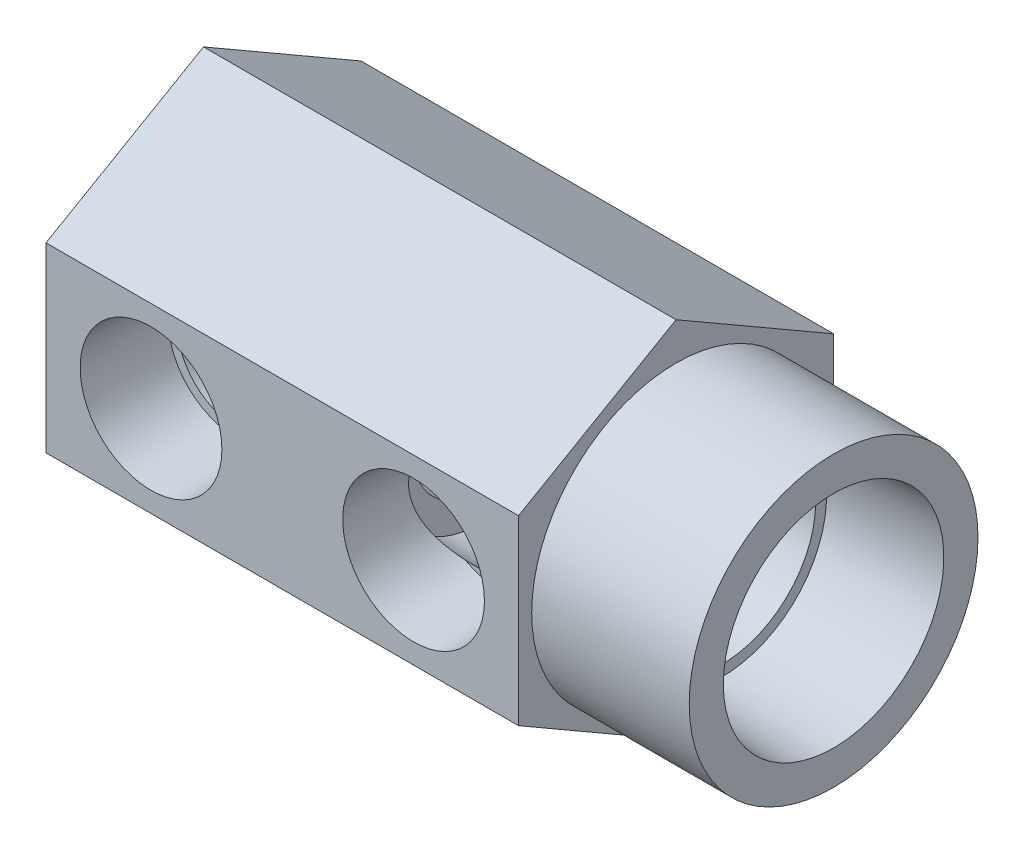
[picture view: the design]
ISO-10303-21;
HEADER;
FILE_DESCRIPTION(('STEP AP214'),'2;1');
FILE_NAME('part.step','',(''),(''),'','','');
FILE_SCHEMA(('AUTOMOTIVE_DESIGN { 1 0 10303 214 1 1 1 1 }'));
ENDSEC;
DATA;
#1=APPLICATION_CONTEXT('core data for automotive mechanical design processes');
#2=APPLICATION_PROTOCOL_DEFINITION('international standard','automotive_design',2000,#1);
#3=PRODUCT_CONTEXT('',#1,'mechanical');
#4=PRODUCT('Part','Part','',(#3));
#5=PRODUCT_RELATED_PRODUCT_CATEGORY('part','',(#4));
#6=PRODUCT_DEFINITION_FORMATION('','',#4);
#7=PRODUCT_DEFINITION_CONTEXT('part definition',#1,'design');
#8=PRODUCT_DEFINITION('design','',#6,#7);
#9=PRODUCT_DEFINITION_SHAPE('','',#8);
#10=(LENGTH_UNIT() NAMED_UNIT(*) SI_UNIT(.MILLI.,.METRE.));
#11=(NAMED_UNIT(*) PLANE_ANGLE_UNIT() SI_UNIT($,.RADIAN.));
#12=(NAMED_UNIT(*) SI_UNIT($,.STERADIAN.) SOLID_ANGLE_UNIT());
#13=UNCERTAINTY_MEASURE_WITH_UNIT(LENGTH_MEASURE(1.E-05),#10,'distance_accuracy_value','');
#14=(GEOMETRIC_REPRESENTATION_CONTEXT(3) GLOBAL_UNCERTAINTY_ASSIGNED_CONTEXT((#13)) GLOBAL_UNIT_ASSIGNED_CONTEXT((#10,
#11,#12)) REPRESENTATION_CONTEXT('',''));
#15=CARTESIAN_POINT('',(0.,0.,0.));
#16=DIRECTION('',(0.,0.,1.));
#17=DIRECTION('',(1.,0.,0.));
#18=AXIS2_PLACEMENT_3D('',#15,#16,#17);
#19=CARTESIAN_POINT('',(76.2,0.,0.));
#20=DIRECTION('',(-1.,0.,0.));
#21=DIRECTION('',(0.,0.,1.));
#22=AXIS2_PLACEMENT_3D('',#19,#20,#21);
#23=PLANE('',#22);
#24=CARTESIAN_POINT('',(76.2,0.,0.));
#25=DIRECTION('',(-1.,0.,0.));
#26=DIRECTION('',(0.,0.,1.));
#27=AXIS2_PLACEMENT_3D('',#24,#25,#26);
#28=CIRCLE('',#27,17.4625);
#29=CARTESIAN_POINT('',(76.2,0.,17.4625));
#30=VERTEX_POINT('',#29);
#31=EDGE_CURVE('E214',#30,#30,#28,.T.);
#32=ORIENTED_EDGE('',*,*,#31,.F.);
#33=EDGE_LOOP('',(#32));
#34=FACE_BOUND('',#33,.T.);
#35=CARTESIAN_POINT('',(76.2,0.,0.));
#36=DIRECTION('',(-1.,0.,0.));
#37=DIRECTION('',(0.,0.,1.));
#38=AXIS2_PLACEMENT_3D('',#35,#36,#37);
#39=CIRCLE('',#38,13.335);
#40=CARTESIAN_POINT('',(76.2,0.,13.335));
#41=VERTEX_POINT('',#40);
#42=EDGE_CURVE('E208',#41,#41,#39,.T.);
#43=ORIENTED_EDGE('',*,*,#42,.T.);
#44=EDGE_LOOP('',(#43));
#45=FACE_BOUND('',#44,.T.);
#46=ADVANCED_FACE('F35',(#34,#45),#23,.F.);
#47=CARTESIAN_POINT('',(57.15,10.9985226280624,19.05));
#48=DIRECTION('',(0.,0.,-1.));
#49=DIRECTION('',(-1.,0.,0.));
#50=AXIS2_PLACEMENT_3D('',#47,#48,#49);
#51=PLANE('',#50);
#52=CARTESIAN_POINT('',(12.7,0.,19.05));
#53=DIRECTION('',(0.,0.,1.));
#54=DIRECTION('',(1.,0.,0.));
#55=AXIS2_PLACEMENT_3D('',#52,#53,#54);
#56=CIRCLE('',#55,8.5725);
#57=CARTESIAN_POINT('',(21.2725,0.,19.05));
#58=VERTEX_POINT('',#57);
#59=EDGE_CURVE('E187',#58,#58,#56,.T.);
#60=ORIENTED_EDGE('',*,*,#59,.F.);
#61=EDGE_LOOP('',(#60));
#62=FACE_BOUND('',#61,.T.);
#63=CARTESIAN_POINT('',(44.45,0.,19.05));
#64=DIRECTION('',(0.,0.,1.));
#65=DIRECTION('',(1.,0.,0.));
#66=AXIS2_PLACEMENT_3D('',#63,#64,#65);
#67=CIRCLE('',#66,8.5725);
#68=CARTESIAN_POINT('',(53.0225,0.,19.05));
#69=VERTEX_POINT('',#68);
#70=EDGE_CURVE('E196',#69,#69,#67,.T.);
#71=ORIENTED_EDGE('',*,*,#70,.F.);
#72=EDGE_LOOP('',(#71));
#73=FACE_BOUND('',#72,.T.);
#74=DIRECTION('',(0.,-1.,0.));
#75=VECTOR('',#74,1.);
#76=CARTESIAN_POINT('',(0.,10.9985226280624,19.05));
#77=LINE('',#76,#75);
#78=CARTESIAN_POINT('',(0.,10.9985226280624,19.05));
#79=VERTEX_POINT('',#78);
#80=CARTESIAN_POINT('',(0.,-10.9985226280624,19.05));
#81=VERTEX_POINT('',#80);
#82=EDGE_CURVE('E217',#79,#81,#77,.T.);
#83=ORIENTED_EDGE('',*,*,#82,.T.);
#84=DIRECTION('',(-1.,0.,0.));
#85=VECTOR('',#84,1.);
#86=CARTESIAN_POINT('',(57.15,-10.9985226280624,19.05));
#87=LINE('',#86,#85);
#88=CARTESIAN_POINT('',(57.15,-10.9985226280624,19.05));
#89=VERTEX_POINT('',#88);
#90=EDGE_CURVE('E222',#89,#81,#87,.T.);
#91=ORIENTED_EDGE('',*,*,#90,.F.);
#92=DIRECTION('',(0.,-1.,0.));
#93=VECTOR('',#92,1.);
#94=CARTESIAN_POINT('',(57.15,10.9985226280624,19.05));
#95=LINE('',#94,#93);
#96=CARTESIAN_POINT('',(57.15,10.9985226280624,19.05));
#97=VERTEX_POINT('',#96);
#98=EDGE_CURVE('E223',#97,#89,#95,.T.);
#99=ORIENTED_EDGE('',*,*,#98,.F.);
#100=DIRECTION('',(-1.,0.,0.));
#101=VECTOR('',#100,1.);
#102=CARTESIAN_POINT('',(57.15,10.9985226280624,19.05));
#103=LINE('',#102,#101);
#104=EDGE_CURVE('E237',#97,#79,#103,.T.);
#105=ORIENTED_EDGE('',*,*,#104,.T.);
#106=EDGE_LOOP('',(#83,#91,#99,#105));
#107=FACE_BOUND('',#106,.T.);
#108=ADVANCED_FACE('F37',(#62,#73,#107),#51,.F.);
#109=CARTESIAN_POINT('',(57.15,-10.9985226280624,19.05));
#110=DIRECTION('',(0.,0.866025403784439,-0.5));
#111=DIRECTION('',(0.,0.5,0.866025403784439));
#112=AXIS2_PLACEMENT_3D('',#109,#110,#111);
#113=PLANE('',#112);
#114=DIRECTION('',(0.,-0.5,-0.866025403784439));
#115=VECTOR('',#114,1.);
#116=CARTESIAN_POINT('',(0.,-10.9985226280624,19.05));
#117=LINE('',#116,#115);
#118=CARTESIAN_POINT('',(0.,-21.9970452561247,0.));
#119=VERTEX_POINT('',#118);
#120=EDGE_CURVE('E240',#81,#119,#117,.T.);
#121=ORIENTED_EDGE('',*,*,#120,.T.);
#122=DIRECTION('',(-1.,0.,0.));
#123=VECTOR('',#122,1.);
#124=CARTESIAN_POINT('',(57.15,-21.9970452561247,0.));
#125=LINE('',#124,#123);
#126=CARTESIAN_POINT('',(57.15,-21.9970452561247,0.));
#127=VERTEX_POINT('',#126);
#128=EDGE_CURVE('E260',#127,#119,#125,.T.);
#129=ORIENTED_EDGE('',*,*,#128,.F.);
#130=DIRECTION('',(0.,-0.5,-0.866025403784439));
#131=VECTOR('',#130,1.);
#132=CARTESIAN_POINT('',(57.15,-10.9985226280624,19.05));
#133=LINE('',#132,#131);
#134=EDGE_CURVE('E226',#89,#127,#133,.T.);
#135=ORIENTED_EDGE('',*,*,#134,.F.);
#136=ORIENTED_EDGE('',*,*,#90,.T.);
#137=EDGE_LOOP('',(#121,#129,#135,#136));
#138=FACE_BOUND('',#137,.T.);
#139=ADVANCED_FACE('F323',(#138),#113,.F.);
#140=CARTESIAN_POINT('',(57.15,-21.9970452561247,0.));
#141=DIRECTION('',(0.,0.866025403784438,0.5));
#142=DIRECTION('',(0.,-0.5,0.866025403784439));
#143=AXIS2_PLACEMENT_3D('',#140,#141,#142);
#144=PLANE('',#143);
#145=DIRECTION('',(0.,0.5,-0.866025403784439));
#146=VECTOR('',#145,1.);
#147=CARTESIAN_POINT('',(0.,-21.9970452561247,0.));
#148=LINE('',#147,#146);
#149=CARTESIAN_POINT('',(0.,-10.9985226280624,-19.05));
#150=VERTEX_POINT('',#149);
#151=EDGE_CURVE('E242',#119,#150,#148,.T.);
#152=ORIENTED_EDGE('',*,*,#151,.T.);
#153=DIRECTION('',(-1.,0.,0.));
#154=VECTOR('',#153,1.);
#155=CARTESIAN_POINT('',(57.15,-10.9985226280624,-19.05));
#156=LINE('',#155,#154);
#157=CARTESIAN_POINT('',(57.15,-10.9985226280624,-19.05));
#158=VERTEX_POINT('',#157);
#159=EDGE_CURVE('E257',#158,#150,#156,.T.);
#160=ORIENTED_EDGE('',*,*,#159,.F.);
#161=DIRECTION('',(0.,0.5,-0.866025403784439));
#162=VECTOR('',#161,1.);
#163=CARTESIAN_POINT('',(57.15,-21.9970452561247,0.));
#164=LINE('',#163,#162);
#165=EDGE_CURVE('E229',#127,#158,#164,.T.);
#166=ORIENTED_EDGE('',*,*,#165,.F.);
#167=ORIENTED_EDGE('',*,*,#128,.T.);
#168=EDGE_LOOP('',(#152,#160,#166,#167));
#169=FACE_BOUND('',#168,.T.);
#170=ADVANCED_FACE('F349',(#169),#144,.F.);
#171=CARTESIAN_POINT('',(57.15,-10.9985226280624,-19.05));
#172=DIRECTION('',(0.,0.,1.));
#173=DIRECTION('',(0.,-1.,0.));
#174=AXIS2_PLACEMENT_3D('',#171,#172,#173);
#175=PLANE('',#174);
#176=CARTESIAN_POINT('',(12.7,0.,-19.05));
#177=DIRECTION('',(0.,0.,-1.));
#178=DIRECTION('',(0.,1.,0.));
#179=AXIS2_PLACEMENT_3D('',#176,#177,#178);
#180=CIRCLE('',#179,8.5725);
#181=CARTESIAN_POINT('',(12.7,8.57250000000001,-19.05));
#182=VERTEX_POINT('',#181);
#183=EDGE_CURVE('E124',#182,#182,#180,.T.);
#184=ORIENTED_EDGE('',*,*,#183,.F.);
#185=EDGE_LOOP('',(#184));
#186=FACE_BOUND('',#185,.T.);
#187=DIRECTION('',(0.,1.,0.));
#188=VECTOR('',#187,1.);
#189=CARTESIAN_POINT('',(0.,-10.9985226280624,-19.05));
#190=LINE('',#189,#188);
#191=CARTESIAN_POINT('',(0.,10.9985226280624,-19.05));
#192=VERTEX_POINT('',#191);
#193=EDGE_CURVE('E244',#150,#192,#190,.T.);
#194=ORIENTED_EDGE('',*,*,#193,.T.);
#195=DIRECTION('',(-1.,0.,0.));
#196=VECTOR('',#195,1.);
#197=CARTESIAN_POINT('',(57.15,10.9985226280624,-19.05));
#198=LINE('',#197,#196);
#199=CARTESIAN_POINT('',(57.15,10.9985226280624,-19.05));
#200=VERTEX_POINT('',#199);
#201=EDGE_CURVE('E254',#200,#192,#198,.T.);
#202=ORIENTED_EDGE('',*,*,#201,.F.);
#203=DIRECTION('',(0.,1.,0.));
#204=VECTOR('',#203,1.);
#205=CARTESIAN_POINT('',(57.15,-10.9985226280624,-19.05));
#206=LINE('',#205,#204);
#207=EDGE_CURVE('E231',#158,#200,#206,.T.);
#208=ORIENTED_EDGE('',*,*,#207,.F.);
#209=ORIENTED_EDGE('',*,*,#159,.T.);
#210=EDGE_LOOP('',(#194,#202,#208,#209));
#211=FACE_BOUND('',#210,.T.);
#212=ADVANCED_FACE('F345',(#186,#211),#175,.F.);
#213=CARTESIAN_POINT('',(57.15,10.9985226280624,-19.05));
#214=DIRECTION('',(0.,-0.866025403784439,0.5));
#215=DIRECTION('',(0.,-0.5,-0.866025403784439));
#216=AXIS2_PLACEMENT_3D('',#213,#214,#215);
#217=PLANE('',#216);
#218=DIRECTION('',(0.,0.5,0.866025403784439));
#219=VECTOR('',#218,1.);
#220=CARTESIAN_POINT('',(0.,10.9985226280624,-19.05));
#221=LINE('',#220,#219);
#222=CARTESIAN_POINT('',(0.,21.9970452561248,0.));
#223=VERTEX_POINT('',#222);
#224=EDGE_CURVE('E246',#192,#223,#221,.T.);
#225=ORIENTED_EDGE('',*,*,#224,.T.);
#226=DIRECTION('',(-1.,0.,0.));
#227=VECTOR('',#226,1.);
#228=CARTESIAN_POINT('',(57.15,21.9970452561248,0.));
#229=LINE('',#228,#227);
#230=CARTESIAN_POINT('',(57.15,21.9970452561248,0.));
#231=VERTEX_POINT('',#230);
#232=EDGE_CURVE('E251',#231,#223,#229,.T.);
#233=ORIENTED_EDGE('',*,*,#232,.F.);
#234=DIRECTION('',(0.,0.5,0.866025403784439));
#235=VECTOR('',#234,1.);
#236=CARTESIAN_POINT('',(57.15,10.9985226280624,-19.05));
#237=LINE('',#236,#235);
#238=EDGE_CURVE('E233',#200,#231,#237,.T.);
#239=ORIENTED_EDGE('',*,*,#238,.F.);
#240=ORIENTED_EDGE('',*,*,#201,.T.);
#241=EDGE_LOOP('',(#225,#233,#239,#240));
#242=FACE_BOUND('',#241,.T.);
#243=ADVANCED_FACE('F341',(#242),#217,.F.);
#244=CARTESIAN_POINT('',(57.15,21.9970452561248,0.));
#245=DIRECTION('',(0.,-0.866025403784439,-0.5));
#246=DIRECTION('',(0.,0.5,-0.866025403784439));
#247=AXIS2_PLACEMENT_3D('',#244,#245,#246);
#248=PLANE('',#247);
#249=DIRECTION('',(0.,-0.5,0.866025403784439));
#250=VECTOR('',#249,1.);
#251=CARTESIAN_POINT('',(0.,21.9970452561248,0.));
#252=LINE('',#251,#250);
#253=EDGE_CURVE('E227',#223,#79,#252,.T.);
#254=ORIENTED_EDGE('',*,*,#253,.T.);
#255=ORIENTED_EDGE('',*,*,#104,.F.);
#256=DIRECTION('',(0.,-0.5,0.866025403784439));
#257=VECTOR('',#256,1.);
#258=CARTESIAN_POINT('',(57.15,21.9970452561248,0.));
#259=LINE('',#258,#257);
#260=EDGE_CURVE('E235',#231,#97,#259,.T.);
#261=ORIENTED_EDGE('',*,*,#260,.F.);
#262=ORIENTED_EDGE('',*,*,#232,.T.);
#263=EDGE_LOOP('',(#254,#255,#261,#262));
#264=FACE_BOUND('',#263,.T.);
#265=ADVANCED_FACE('F334',(#264),#248,.F.);
#266=CARTESIAN_POINT('',(57.15,-10.9985226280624,19.05));
#267=DIRECTION('',(1.,0.,0.));
#268=DIRECTION('',(0.,0.,-1.));
#269=AXIS2_PLACEMENT_3D('',#266,#267,#268);
#270=PLANE('',#269);
#271=CARTESIAN_POINT('',(57.15,0.,0.));
#272=DIRECTION('',(1.,0.,0.));
#273=DIRECTION('',(0.,0.,-1.));
#274=AXIS2_PLACEMENT_3D('',#271,#272,#273);
#275=CIRCLE('',#274,17.4625);
#276=CARTESIAN_POINT('',(57.15,0.,17.4625));
#277=VERTEX_POINT('',#276);
#278=EDGE_CURVE('E218',#277,#277,#275,.T.);
#279=ORIENTED_EDGE('',*,*,#278,.F.);
#280=EDGE_LOOP('',(#279));
#281=FACE_BOUND('',#280,.T.);
#282=ORIENTED_EDGE('',*,*,#98,.T.);
#283=ORIENTED_EDGE('',*,*,#134,.T.);
#284=ORIENTED_EDGE('',*,*,#165,.T.);
#285=ORIENTED_EDGE('',*,*,#207,.T.);
#286=ORIENTED_EDGE('',*,*,#238,.T.);
#287=ORIENTED_EDGE('',*,*,#260,.T.);
#288=EDGE_LOOP('',(#282,#283,#284,#285,#286,#287));
#289=FACE_BOUND('',#288,.T.);
#290=ADVANCED_FACE('F331',(#281,#289),#270,.T.);
#291=CARTESIAN_POINT('',(0.,-10.9985226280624,19.05));
#292=DIRECTION('',(1.,0.,0.));
#293=DIRECTION('',(0.,0.,-1.));
#294=AXIS2_PLACEMENT_3D('',#291,#292,#293);
#295=PLANE('',#294);
#296=ORIENTED_EDGE('',*,*,#82,.F.);
#297=ORIENTED_EDGE('',*,*,#253,.F.);
#298=ORIENTED_EDGE('',*,*,#224,.F.);
#299=ORIENTED_EDGE('',*,*,#193,.F.);
#300=ORIENTED_EDGE('',*,*,#151,.F.);
#301=ORIENTED_EDGE('',*,*,#120,.F.);
#302=EDGE_LOOP('',(#296,#297,#298,#299,#300,#301));
#303=FACE_BOUND('',#302,.T.);
#304=ADVANCED_FACE('F329',(#303),#295,.F.);
#305=CARTESIAN_POINT('',(76.2,0.,0.));
#306=DIRECTION('',(-1.,0.,0.));
#307=DIRECTION('',(0.,0.,1.));
#308=AXIS2_PLACEMENT_3D('',#305,#306,#307);
#309=CYLINDRICAL_SURFACE('',#308,17.4625);
#310=CARTESIAN_POINT('',(57.15,0.,17.4625));
#311=CARTESIAN_POINT('',(57.3484375,0.,17.4625));
#312=CARTESIAN_POINT('',(57.546875,0.,17.4625));
#313=CARTESIAN_POINT('',(57.94375,0.,17.4625));
#314=CARTESIAN_POINT('',(58.1421875,0.,17.4625));
#315=CARTESIAN_POINT('',(58.5390625,0.,17.4625));
#316=CARTESIAN_POINT('',(58.7375,0.,17.4625));
#317=CARTESIAN_POINT('',(59.134375,0.,17.4625));
#318=CARTESIAN_POINT('',(59.3328125,0.,17.4625));
#319=CARTESIAN_POINT('',(59.7296875,0.,17.4625));
#320=CARTESIAN_POINT('',(59.928125,0.,17.4625));
#321=CARTESIAN_POINT('',(60.325,0.,17.4625));
#322=CARTESIAN_POINT('',(60.5234375,0.,17.4625));
#323=CARTESIAN_POINT('',(60.9203125,0.,17.4625));
#324=CARTESIAN_POINT('',(61.11875,0.,17.4625));
#325=CARTESIAN_POINT('',(61.515625,0.,17.4625));
#326=CARTESIAN_POINT('',(61.7140625,0.,17.4625));
#327=CARTESIAN_POINT('',(62.1109375,0.,17.4625));
#328=CARTESIAN_POINT('',(62.309375,0.,17.4625));
#329=CARTESIAN_POINT('',(62.70625,0.,17.4625));
#330=CARTESIAN_POINT('',(62.9046875,0.,17.4625));
#331=CARTESIAN_POINT('',(63.3015625,0.,17.4625));
#332=CARTESIAN_POINT('',(63.5,0.,17.4625));
#333=CARTESIAN_POINT('',(63.896875,0.,17.4625));
#334=CARTESIAN_POINT('',(64.0953125,0.,17.4625));
#335=CARTESIAN_POINT('',(64.4921875,0.,17.4625));
#336=CARTESIAN_POINT('',(64.690625,0.,17.4625));
#337=CARTESIAN_POINT('',(65.0875,0.,17.4625));
#338=CARTESIAN_POINT('',(65.2859375,0.,17.4625));
#339=CARTESIAN_POINT('',(65.6828125,0.,17.4625));
#340=CARTESIAN_POINT('',(65.88125,0.,17.4625));
#341=CARTESIAN_POINT('',(66.278125,0.,17.4625));
#342=CARTESIAN_POINT('',(66.4765625,0.,17.4625));
#343=CARTESIAN_POINT('',(66.8734375,0.,17.4625));
#344=CARTESIAN_POINT('',(67.071875,0.,17.4625));
#345=CARTESIAN_POINT('',(67.46875,0.,17.4625));
#346=CARTESIAN_POINT('',(67.6671875,0.,17.4625));
#347=CARTESIAN_POINT('',(68.0640625,0.,17.4625));
#348=CARTESIAN_POINT('',(68.2625,0.,17.4625));
#349=CARTESIAN_POINT('',(68.659375,0.,17.4625));
#350=CARTESIAN_POINT('',(68.8578125,0.,17.4625));
#351=CARTESIAN_POINT('',(69.2546875,0.,17.4625));
#352=CARTESIAN_POINT('',(69.453125,0.,17.4625));
#353=CARTESIAN_POINT('',(69.85,0.,17.4625));
#354=CARTESIAN_POINT('',(70.0484375,0.,17.4625));
#355=CARTESIAN_POINT('',(70.4453125,0.,17.4625));
#356=CARTESIAN_POINT('',(70.64375,0.,17.4625));
#357=CARTESIAN_POINT('',(71.040625,0.,17.4625));
#358=CARTESIAN_POINT('',(71.2390625,0.,17.4625));
#359=CARTESIAN_POINT('',(71.6359375,0.,17.4625));
#360=CARTESIAN_POINT('',(71.834375,0.,17.4625));
#361=CARTESIAN_POINT('',(72.23125,0.,17.4625));
#362=CARTESIAN_POINT('',(72.4296875,0.,17.4625));
#363=CARTESIAN_POINT('',(72.8265625,0.,17.4625));
#364=CARTESIAN_POINT('',(73.025,0.,17.4625));
#365=CARTESIAN_POINT('',(73.421875,0.,17.4625));
#366=CARTESIAN_POINT('',(73.6203125,0.,17.4625));
#367=CARTESIAN_POINT('',(74.0171875,0.,17.4625));
#368=CARTESIAN_POINT('',(74.215625,0.,17.4625));
#369=CARTESIAN_POINT('',(74.6125,0.,17.4625));
#370=CARTESIAN_POINT('',(74.8109375,0.,17.4625));
#371=CARTESIAN_POINT('',(75.2078125,0.,17.4625));
#372=CARTESIAN_POINT('',(75.40625,0.,17.4625));
#373=CARTESIAN_POINT('',(75.803125,0.,17.4625));
#374=CARTESIAN_POINT('',(76.0015625,0.,17.4625));
#375=CARTESIAN_POINT('',(76.2,0.,17.4625));
#376=B_SPLINE_CURVE_WITH_KNOTS('',3,(#310,#311,#312,#313,#314,#315,#316,#317,#318,#319,#320,
#321,#322,#323,#324,#325,#326,#327,#328,#329,#330,#331,#332,#333,#334,#335,#336,#337,#338,#339,
#340,#341,#342,#343,#344,#345,#346,#347,#348,#349,#350,#351,#352,#353,#354,#355,#356,#357,#358,
#359,#360,#361,#362,#363,#364,#365,#366,#367,#368,#369,#370,#371,#372,#373,#374,#375),
.UNSPECIFIED.,.F.,.F.,(4,2,2,2,2,2,2,2,2,2,2,2,2,2,2,2,2,2,2,2,2,2,2,2,2,2,2,2,2,2,2,2,4),(0.,
0.5953125,1.190625,1.7859375,2.38125,2.9765625,3.571875,4.1671875,4.7625,5.3578125,5.953125,
6.5484375,7.14375,7.7390625,8.334375,8.92968750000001,9.52500000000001,10.1203125,10.715625,
11.3109375,11.90625,12.5015625,13.096875,13.6921875,14.2875,14.8828125,15.478125,16.0734375,
16.66875,17.2640625,17.859375,18.4546875,19.05),.UNSPECIFIED.);
#377=EDGE_CURVE('BSEAM308',#277,#30,#376,.T.);
#378=ORIENTED_EDGE('',*,*,#278,.T.);
#379=ORIENTED_EDGE('',*,*,#31,.T.);
#380=ORIENTED_EDGE('',*,*,#377,.T.);
#381=ORIENTED_EDGE('',*,*,#377,.F.);
#382=EDGE_LOOP('',(#378,#380,#379,#381));
#383=FACE_BOUND('',#382,.T.);
#384=ADVANCED_FACE('F308',(#383),#309,.T.);
#385=CARTESIAN_POINT('',(62.7126,11.3157,0.));
#386=DIRECTION('',(1.,0.,0.));
#387=DIRECTION('',(0.,0.,-1.));
#388=AXIS2_PLACEMENT_3D('',#385,#386,#387);
#389=PLANE('',#388);
#390=CARTESIAN_POINT('',(62.7126,0.,0.));
#391=DIRECTION('',(-1.,0.,0.));
#392=DIRECTION('',(0.,0.,1.));
#393=AXIS2_PLACEMENT_3D('',#390,#391,#392);
#394=CIRCLE('',#393,11.3157);
#395=CARTESIAN_POINT('',(62.7126,0.,11.3157));
#396=VERTEX_POINT('',#395);
#397=EDGE_CURVE('E202',#396,#396,#394,.T.);
#398=ORIENTED_EDGE('',*,*,#397,.T.);
#399=EDGE_LOOP('',(#398));
#400=FACE_BOUND('',#399,.T.);
#401=CARTESIAN_POINT('',(62.7126,0.,0.));
#402=DIRECTION('',(-1.,0.,0.));
#403=DIRECTION('',(0.,0.,1.));
#404=AXIS2_PLACEMENT_3D('',#401,#402,#403);
#405=CIRCLE('',#404,12.6281553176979);
#406=CARTESIAN_POINT('',(62.7126,0.,12.6281553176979));
#407=VERTEX_POINT('',#406);
#408=EDGE_CURVE('E211',#407,#407,#405,.T.);
#409=ORIENTED_EDGE('',*,*,#408,.F.);
#410=EDGE_LOOP('',(#409));
#411=FACE_BOUND('',#410,.T.);
#412=ADVANCED_FACE('F304',(#400,#411),#389,.T.);
#413=CARTESIAN_POINT('',(76.2,0.,0.));
#414=DIRECTION('',(1.,0.,0.));
#415=DIRECTION('',(0.,0.,-1.));
#416=AXIS2_PLACEMENT_3D('',#413,#414,#415);
#417=CONICAL_SURFACE('',#416,13.335,0.0523598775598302);
#418=ORIENTED_EDGE('',*,*,#408,.T.);
#419=EDGE_LOOP('',(#418));
#420=FACE_BOUND('',#419,.T.);
#421=ORIENTED_EDGE('',*,*,#42,.F.);
#422=EDGE_LOOP('',(#421));
#423=FACE_BOUND('',#422,.T.);
#424=ADVANCED_FACE('F307',(#420,#423),#417,.F.);
#425=CARTESIAN_POINT('',(33.3375,0.,0.));
#426=DIRECTION('',(1.,0.,0.));
#427=DIRECTION('',(0.,0.,-1.));
#428=AXIS2_PLACEMENT_3D('',#425,#426,#427);
#429=PLANE('',#428);
#430=CARTESIAN_POINT('',(33.3375,0.,0.));
#431=DIRECTION('',(1.,0.,0.));
#432=DIRECTION('',(0.,0.,-1.));
#433=AXIS2_PLACEMENT_3D('',#430,#431,#432);
#434=CIRCLE('',#433,7.93749999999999);
#435=CARTESIAN_POINT('',(33.3375,0.,-7.93749999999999));
#436=VERTEX_POINT('',#435);
#437=EDGE_CURVE('E39',#436,#436,#434,.T.);
#438=ORIENTED_EDGE('',*,*,#437,.F.);
#439=EDGE_LOOP('',(#438));
#440=FACE_BOUND('',#439,.T.);
#441=CARTESIAN_POINT('',(33.3375,0.,0.));
#442=DIRECTION('',(-1.,0.,0.));
#443=DIRECTION('',(0.,0.,1.));
#444=AXIS2_PLACEMENT_3D('',#441,#442,#443);
#445=CIRCLE('',#444,11.3157);
#446=CARTESIAN_POINT('',(33.3375,0.,11.3157));
#447=VERTEX_POINT('',#446);
#448=EDGE_CURVE('E205',#447,#447,#445,.T.);
#449=ORIENTED_EDGE('',*,*,#448,.F.);
#450=EDGE_LOOP('',(#449));
#451=FACE_BOUND('',#450,.T.);
#452=ADVANCED_FACE('F299',(#440,#451),#429,.T.);
#453=CARTESIAN_POINT('',(0.,0.,0.));
#454=DIRECTION('',(-1.,0.,0.));
#455=DIRECTION('',(0.,0.,1.));
#456=AXIS2_PLACEMENT_3D('',#453,#454,#455);
#457=CYLINDRICAL_SURFACE('',#456,11.3157);
#458=CARTESIAN_POINT('',(48.4832482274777,7.21202423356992,8.71962000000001));
#459=CARTESIAN_POINT('',(48.5925124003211,7.15260118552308,8.76877049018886));
#460=CARTESIAN_POINT('',(48.7001386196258,7.09091491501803,8.81876664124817));
#461=CARTESIAN_POINT('',(48.9120877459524,6.96309485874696,8.92003476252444));
#462=CARTESIAN_POINT('',(49.0164109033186,6.89696141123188,8.97130663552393));
#463=CARTESIAN_POINT('',(49.324389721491,6.6920075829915,9.12641430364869));
#464=CARTESIAN_POINT('',(49.5230754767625,6.54662240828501,9.23155163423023));
#465=CARTESIAN_POINT('',(49.9084902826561,6.23742271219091,9.44325653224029));
#466=CARTESIAN_POINT('',(50.0950828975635,6.0734413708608,9.54982801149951));
#467=CARTESIAN_POINT('',(50.4534552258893,5.72859397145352,9.76058958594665));
#468=CARTESIAN_POINT('',(50.6252350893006,5.54772808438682,9.86477970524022));
#469=CARTESIAN_POINT('',(50.95334425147,5.16902744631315,10.0683940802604));
#470=CARTESIAN_POINT('',(51.1096332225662,4.9711507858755,10.1678055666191));
#471=CARTESIAN_POINT('',(51.4048898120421,4.5593498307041,10.3590018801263));
#472=CARTESIAN_POINT('',(51.5438562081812,4.34542440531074,10.4507861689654));
#473=CARTESIAN_POINT('',(51.8021903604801,3.90338216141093,10.6237828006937));
#474=CARTESIAN_POINT('',(51.9216413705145,3.67533167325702,10.7050397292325));
#475=CARTESIAN_POINT('',(52.1397533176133,3.20558061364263,10.854953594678));
#476=CARTESIAN_POINT('',(52.2384234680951,2.96388615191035,10.9236161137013));
#477=CARTESIAN_POINT('',(52.3882932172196,2.53902338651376,11.0286830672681));
#478=CARTESIAN_POINT('',(52.445021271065,2.35868013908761,11.0687148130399));
#479=CARTESIAN_POINT('',(52.5461470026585,1.99295086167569,11.1403728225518));
#480=CARTESIAN_POINT('',(52.5905474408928,1.80756597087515,11.1720009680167));
#481=CARTESIAN_POINT('',(52.6664301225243,1.43287943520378,11.226208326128));
#482=CARTESIAN_POINT('',(52.6979134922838,1.24357813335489,11.2487883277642));
#483=CARTESIAN_POINT('',(52.7475140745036,0.862328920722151,11.284418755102));
#484=CARTESIAN_POINT('',(52.7656308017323,0.670380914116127,11.2974688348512));
#485=CARTESIAN_POINT('',(52.7882410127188,0.28487061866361,11.313762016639));
#486=CARTESIAN_POINT('',(52.7927065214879,0.0913058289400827,11.3169849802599));
#487=CARTESIAN_POINT('',(52.7878647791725,-0.295559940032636,11.3134932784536));
#488=CARTESIAN_POINT('',(52.7785575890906,-0.488860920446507,11.3067786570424));
#489=CARTESIAN_POINT('',(52.7463150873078,-0.873744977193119,11.2835637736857));
#490=CARTESIAN_POINT('',(52.7233783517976,-1.06532787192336,11.2670624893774));
#491=CARTESIAN_POINT('',(52.6642226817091,-1.44536483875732,11.2246401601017));
#492=CARTESIAN_POINT('',(52.6280037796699,-1.63381891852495,11.1987191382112));
#493=CARTESIAN_POINT('',(52.5440099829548,-2.00105020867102,11.1388729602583));
#494=CARTESIAN_POINT('',(52.4965927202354,-2.17995022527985,11.1051961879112));
#495=CARTESIAN_POINT('',(52.3902683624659,-2.53269300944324,11.0300982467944));
#496=CARTESIAN_POINT('',(52.3313572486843,-2.70653398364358,10.988674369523));
#497=CARTESIAN_POINT('',(52.2027106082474,-3.04823801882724,10.8988304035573));
#498=CARTESIAN_POINT('',(52.1329779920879,-3.21610267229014,10.8504121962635));
#499=CARTESIAN_POINT('',(51.9833334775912,-3.54528615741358,10.74736285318));
#500=CARTESIAN_POINT('',(51.9034179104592,-3.70660260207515,10.6927294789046));
#501=CARTESIAN_POINT('',(51.6304772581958,-4.21511504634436,10.5079429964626));
#502=CARTESIAN_POINT('',(51.4185805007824,-4.54853539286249,10.3670960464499));
#503=CARTESIAN_POINT('',(50.9538811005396,-5.1770594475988,10.0679980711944));
#504=CARTESIAN_POINT('',(50.7010294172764,-5.47211644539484,9.90972625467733));
#505=CARTESIAN_POINT('',(50.2869266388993,-5.89231855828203,9.66199714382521));
#506=CARTESIAN_POINT('',(50.1385941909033,-6.03205879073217,9.57522276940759));
#507=CARTESIAN_POINT('',(49.8322222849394,-6.30008554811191,9.40103824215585));
#508=CARTESIAN_POINT('',(49.6741827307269,-6.42837195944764,9.31362808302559));
#509=CARTESIAN_POINT('',(49.3492433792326,-6.67287312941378,9.14003397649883));
#510=CARTESIAN_POINT('',(49.1823706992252,-6.78912192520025,9.05384720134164));
#511=CARTESIAN_POINT('',(48.8395561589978,-7.00964171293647,8.88422371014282));
#512=CARTESIAN_POINT('',(48.6636139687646,-7.11391226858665,8.80078709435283));
#513=CARTESIAN_POINT('',(48.4832482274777,-7.21202423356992,8.71962));
#514=B_SPLINE_CURVE_WITH_KNOTS('',3,(#458,#459,#460,#461,#462,#463,#464,#465,#466,#467,#468,
#469,#470,#471,#472,#473,#474,#475,#476,#477,#478,#479,#480,#481,#482,#483,#484,#485,#486,#487,
#488,#489,#490,#491,#492,#493,#494,#495,#496,#497,#498,#499,#500,#501,#502,#503,#504,#505,#506,
#507,#508,#509,#510,#511,#512,#513),.UNSPECIFIED.,.F.,.F.,(4,2,2,2,2,2,2,2,2,2,2,2,2,2,2,2,2,2,
2,2,2,2,2,2,2,2,2,4),(0.,0.401138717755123,0.802246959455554,1.60438729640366,2.41439762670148,
3.22439975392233,4.03645804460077,4.84857359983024,5.65712865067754,6.46532446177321,
7.04448228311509,7.62351031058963,8.20248783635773,8.78148637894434,9.36167065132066,
9.94185235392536,10.5220946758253,11.1023355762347,11.66608787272,12.2300376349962,
12.793835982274,13.3578380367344,14.6111296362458,15.8659332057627,16.5299841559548,
17.1940416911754,17.8561671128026,18.5183166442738),.UNSPECIFIED.);
#515=CARTESIAN_POINT('',(48.4836928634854,7.2117824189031,8.71982000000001));
#516=VERTEX_POINT('',#515);
#517=CARTESIAN_POINT('',(48.4836928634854,-7.2117824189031,8.71982000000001));
#518=VERTEX_POINT('',#517);
#519=EDGE_CURVE('E118',#516,#518,#514,.T.);
#520=ORIENTED_EDGE('',*,*,#519,.F.);
#521=DIRECTION('',(-1.,0.,0.));
#522=VECTOR('',#521,1.);
#523=CARTESIAN_POINT('',(0.,7.2117824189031,8.71982000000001));
#524=LINE('',#523,#522);
#525=CARTESIAN_POINT('',(40.4163071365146,7.2117824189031,8.71982000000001));
#526=VERTEX_POINT('',#525);
#527=EDGE_CURVE('E271',#526,#516,#524,.F.);
#528=ORIENTED_EDGE('',*,*,#527,.F.);
#529=CARTESIAN_POINT('',(40.4167517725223,-7.21202423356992,8.71962000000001));
#530=CARTESIAN_POINT('',(40.3074875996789,-7.15260118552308,8.76877049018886));
#531=CARTESIAN_POINT('',(40.1998613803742,-7.09091491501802,8.81876664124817));
#532=CARTESIAN_POINT('',(39.9879122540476,-6.96309485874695,8.92003476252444));
#533=CARTESIAN_POINT('',(39.8835890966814,-6.89696141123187,8.97130663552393));
#534=CARTESIAN_POINT('',(39.575610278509,-6.6920075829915,9.12641430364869));
#535=CARTESIAN_POINT('',(39.3769245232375,-6.54662240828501,9.23155163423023));
#536=CARTESIAN_POINT('',(38.9915097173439,-6.2374227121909,9.44325653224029));
#537=CARTESIAN_POINT('',(38.8049171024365,-6.0734413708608,9.54982801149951));
#538=CARTESIAN_POINT('',(38.4465447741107,-5.72859397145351,9.76058958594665));
#539=CARTESIAN_POINT('',(38.2747649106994,-5.54772808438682,9.86477970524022));
#540=CARTESIAN_POINT('',(37.94665574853,-5.16902744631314,10.0683940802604));
#541=CARTESIAN_POINT('',(37.7903667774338,-4.97115078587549,10.1678055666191));
#542=CARTESIAN_POINT('',(37.4951101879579,-4.55934983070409,10.3590018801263));
#543=CARTESIAN_POINT('',(37.3561437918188,-4.34542440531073,10.4507861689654));
#544=CARTESIAN_POINT('',(37.0978096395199,-3.90338216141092,10.6237828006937));
#545=CARTESIAN_POINT('',(36.9783586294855,-3.67533167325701,10.7050397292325));
#546=CARTESIAN_POINT('',(36.7602466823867,-3.20558061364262,10.854953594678));
#547=CARTESIAN_POINT('',(36.6615765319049,-2.96388615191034,10.9236161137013));
#548=CARTESIAN_POINT('',(36.5117067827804,-2.53902338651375,11.0286830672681));
#549=CARTESIAN_POINT('',(36.4549787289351,-2.3586801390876,11.0687148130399));
#550=CARTESIAN_POINT('',(36.3538529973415,-1.99295086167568,11.1403728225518));
#551=CARTESIAN_POINT('',(36.3094525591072,-1.80756597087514,11.1720009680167));
#552=CARTESIAN_POINT('',(36.2335698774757,-1.43287943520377,11.226208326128));
#553=CARTESIAN_POINT('',(36.2020865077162,-1.24357813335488,11.2487883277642));
#554=CARTESIAN_POINT('',(36.1524859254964,-0.862328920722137,11.284418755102));
#555=CARTESIAN_POINT('',(36.1343691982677,-0.670380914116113,11.2974688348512));
#556=CARTESIAN_POINT('',(36.1117589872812,-0.284870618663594,11.313762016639));
#557=CARTESIAN_POINT('',(36.1072934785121,-0.0913058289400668,11.3169849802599));
#558=CARTESIAN_POINT('',(36.1121352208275,0.295559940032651,11.3134932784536));
#559=CARTESIAN_POINT('',(36.1214424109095,0.488860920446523,11.3067786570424));
#560=CARTESIAN_POINT('',(36.1536849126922,0.873744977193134,11.2835637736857));
#561=CARTESIAN_POINT('',(36.1766216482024,1.06532787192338,11.2670624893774));
#562=CARTESIAN_POINT('',(36.2357773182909,1.44536483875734,11.2246401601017));
#563=CARTESIAN_POINT('',(36.2719962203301,1.63381891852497,11.1987191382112));
#564=CARTESIAN_POINT('',(36.3559900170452,2.00105020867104,11.1388729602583));
#565=CARTESIAN_POINT('',(36.4034072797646,2.17995022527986,11.1051961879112));
#566=CARTESIAN_POINT('',(36.5097316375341,2.53269300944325,11.0300982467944));
#567=CARTESIAN_POINT('',(36.5686427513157,2.70653398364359,10.988674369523));
#568=CARTESIAN_POINT('',(36.6972893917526,3.04823801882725,10.8988304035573));
#569=CARTESIAN_POINT('',(36.7670220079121,3.21610267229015,10.8504121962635));
#570=CARTESIAN_POINT('',(36.9166665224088,3.54528615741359,10.74736285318));
#571=CARTESIAN_POINT('',(36.9965820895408,3.70660260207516,10.6927294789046));
#572=CARTESIAN_POINT('',(37.2695227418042,4.21511504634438,10.5079429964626));
#573=CARTESIAN_POINT('',(37.4814194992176,4.5485353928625,10.3670960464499));
#574=CARTESIAN_POINT('',(37.9461188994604,5.17705944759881,10.0679980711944));
#575=CARTESIAN_POINT('',(38.1989705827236,5.47211644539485,9.90972625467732));
#576=CARTESIAN_POINT('',(38.6130733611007,5.89231855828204,9.6619971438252));
#577=CARTESIAN_POINT('',(38.7614058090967,6.03205879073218,9.57522276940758));
#578=CARTESIAN_POINT('',(39.0677777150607,6.30008554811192,9.40103824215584));
#579=CARTESIAN_POINT('',(39.2258172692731,6.42837195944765,9.31362808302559));
#580=CARTESIAN_POINT('',(39.5507566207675,6.67287312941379,9.14003397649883));
#581=CARTESIAN_POINT('',(39.7176293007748,6.78912192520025,9.05384720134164));
#582=CARTESIAN_POINT('',(40.0604438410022,7.00964171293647,8.88422371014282));
#583=CARTESIAN_POINT('',(40.2363860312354,7.11391226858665,8.80078709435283));
#584=CARTESIAN_POINT('',(40.4167517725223,7.21202423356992,8.71962));
#585=B_SPLINE_CURVE_WITH_KNOTS('',3,(#529,#530,#531,#532,#533,#534,#535,#536,#537,#538,#539,
#540,#541,#542,#543,#544,#545,#546,#547,#548,#549,#550,#551,#552,#553,#554,#555,#556,#557,#558,
#559,#560,#561,#562,#563,#564,#565,#566,#567,#568,#569,#570,#571,#572,#573,#574,#575,#576,#577,
#578,#579,#580,#581,#582,#583,#584),.UNSPECIFIED.,.F.,.F.,(4,2,2,2,2,2,2,2,2,2,2,2,2,2,2,2,2,2,
2,2,2,2,2,2,2,2,2,4),(0.,0.401138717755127,0.802246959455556,1.60438729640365,2.41439762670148,
3.22439975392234,4.03645804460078,4.84857359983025,5.65712865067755,6.46532446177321,
7.04448228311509,7.62351031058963,8.20248783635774,8.78148637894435,9.36167065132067,
9.94185235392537,10.5220946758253,11.1023355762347,11.66608787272,12.2300376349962,
12.793835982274,13.3578380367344,14.6111296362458,15.8659332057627,16.5299841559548,
17.1940416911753,17.8561671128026,18.5183166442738),.UNSPECIFIED.);
#586=CARTESIAN_POINT('',(40.4163071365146,-7.2117824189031,8.71982000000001));
#587=VERTEX_POINT('',#586);
#588=EDGE_CURVE('E221',#587,#526,#585,.T.);
#589=ORIENTED_EDGE('',*,*,#588,.F.);
#590=DIRECTION('',(-1.,0.,0.));
#591=VECTOR('',#590,1.);
#592=CARTESIAN_POINT('',(0.,-7.2117824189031,8.71982000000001));
#593=LINE('',#592,#591);
#594=EDGE_CURVE('E286',#518,#587,#593,.T.);
#595=ORIENTED_EDGE('',*,*,#594,.F.);
#596=EDGE_LOOP('',(#520,#528,#589,#595));
#597=FACE_BOUND('',#596,.T.);
#598=ORIENTED_EDGE('',*,*,#448,.T.);
#599=EDGE_LOOP('',(#598));
#600=FACE_BOUND('',#599,.T.);
#601=ORIENTED_EDGE('',*,*,#397,.F.);
#602=EDGE_LOOP('',(#601));
#603=FACE_BOUND('',#602,.T.);
#604=ADVANCED_FACE('F273',(#597,#600,#603),#457,.F.);
#605=CARTESIAN_POINT('',(51.5874,0.,8.71982000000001));
#606=DIRECTION('',(0.,0.,-1.));
#607=DIRECTION('',(-1.,0.,0.));
#608=AXIS2_PLACEMENT_3D('',#605,#606,#607);
#609=PLANE('',#608);
#610=ORIENTED_EDGE('',*,*,#594,.T.);
#611=CARTESIAN_POINT('',(44.45,0.,8.71982000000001));
#612=DIRECTION('',(0.,0.,1.));
#613=DIRECTION('',(1.,0.,0.));
#614=AXIS2_PLACEMENT_3D('',#611,#612,#613);
#615=CIRCLE('',#614,8.26320057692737);
#616=EDGE_CURVE('E59',#587,#518,#615,.T.);
#617=ORIENTED_EDGE('',*,*,#616,.T.);
#618=EDGE_LOOP('',(#610,#617));
#619=FACE_BOUND('',#618,.T.);
#620=ADVANCED_FACE('F298',(#619),#609,.F.);
#621=ORIENTED_EDGE('',*,*,#527,.T.);
#622=EDGE_CURVE('E199',#516,#526,#615,.T.);
#623=ORIENTED_EDGE('',*,*,#622,.T.);
#624=EDGE_LOOP('',(#621,#623));
#625=FACE_BOUND('',#624,.T.);
#626=ADVANCED_FACE('F280',(#625),#609,.F.);
#627=CARTESIAN_POINT('',(44.45,0.,19.05));
#628=DIRECTION('',(0.,0.,1.));
#629=DIRECTION('',(1.,0.,0.));
#630=AXIS2_PLACEMENT_3D('',#627,#628,#629);
#631=CONICAL_SURFACE('',#630,8.5725,0.0299323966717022);
#632=ORIENTED_EDGE('',*,*,#519,.T.);
#633=ORIENTED_EDGE('',*,*,#616,.F.);
#634=ORIENTED_EDGE('',*,*,#588,.T.);
#635=ORIENTED_EDGE('',*,*,#622,.F.);
#636=EDGE_LOOP('',(#632,#633,#634,#635));
#637=FACE_BOUND('',#636,.T.);
#638=ORIENTED_EDGE('',*,*,#70,.T.);
#639=EDGE_LOOP('',(#638));
#640=FACE_BOUND('',#639,.T.);
#641=ADVANCED_FACE('F277',(#637,#640),#631,.F.);
#642=CARTESIAN_POINT('',(12.7,0.,19.05));
#643=DIRECTION('',(0.,0.,1.));
#644=DIRECTION('',(1.,0.,0.));
#645=AXIS2_PLACEMENT_3D('',#642,#643,#644);
#646=CYLINDRICAL_SURFACE('',#645,7.13740000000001);
#647=CARTESIAN_POINT('',(12.7,7.13740000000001,1.72225752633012));
#648=CARTESIAN_POINT('',(12.7595870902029,7.13740780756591,1.72219425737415));
#649=CARTESIAN_POINT('',(12.8191089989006,7.13665371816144,1.72535095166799));
#650=CARTESIAN_POINT('',(12.9373255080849,7.13369560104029,1.73755665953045));
#651=CARTESIAN_POINT('',(12.996022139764,7.1314961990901,1.74658687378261));
#652=CARTESIAN_POINT('',(13.1679033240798,7.12295687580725,1.78120041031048));
#653=CARTESIAN_POINT('',(13.2794774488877,7.11466879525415,1.81435476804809));
#654=CARTESIAN_POINT('',(13.4789752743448,7.09535627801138,1.88832491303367));
#655=CARTESIAN_POINT('',(13.5678044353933,7.08499166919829,1.92703275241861));
#656=CARTESIAN_POINT('',(13.7417729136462,7.06150716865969,2.01138947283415));
#657=CARTESIAN_POINT('',(13.8269092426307,7.04838509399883,2.05704384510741));
#658=CARTESIAN_POINT('',(13.9951261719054,7.01943851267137,2.15376824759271));
#659=CARTESIAN_POINT('',(14.0781618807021,7.00357904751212,2.20490461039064));
#660=CARTESIAN_POINT('',(14.2415025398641,6.969447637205,2.31052718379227));
#661=CARTESIAN_POINT('',(14.3218083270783,6.95117643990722,2.36501235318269));
#662=CARTESIAN_POINT('',(14.5219562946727,6.9020636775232,2.50564353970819));
#663=CARTESIAN_POINT('',(14.6403255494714,6.86967276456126,2.59333965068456));
#664=CARTESIAN_POINT('',(14.8731228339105,6.7996160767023,2.77183896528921));
#665=CARTESIAN_POINT('',(14.9875493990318,6.76194836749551,2.86264329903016));
#666=CARTESIAN_POINT('',(15.2132879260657,6.68133530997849,3.04605562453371));
#667=CARTESIAN_POINT('',(15.3245960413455,6.63838376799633,3.13866562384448));
#668=CARTESIAN_POINT('',(15.5443880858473,6.54721927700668,3.32465173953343));
#669=CARTESIAN_POINT('',(15.6528716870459,6.49900572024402,3.41802794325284));
#670=CARTESIAN_POINT('',(15.973744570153,6.34673745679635,3.69763002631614));
#671=CARTESIAN_POINT('',(16.1823413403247,6.23477367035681,3.88398153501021));
#672=CARTESIAN_POINT('',(16.5895359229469,5.98919216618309,4.25292562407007));
#673=CARTESIAN_POINT('',(16.7881416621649,5.85559198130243,4.43552111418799));
#674=CARTESIAN_POINT('',(17.1351778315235,5.59540755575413,4.75748883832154));
#675=CARTESIAN_POINT('',(17.2855741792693,5.47295915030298,4.89807499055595));
#676=CARTESIAN_POINT('',(17.5786935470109,5.21336629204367,5.17352108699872));
#677=CARTESIAN_POINT('',(17.7214155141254,5.07621983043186,5.30838024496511));
#678=CARTESIAN_POINT('',(18.1360240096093,4.64240256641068,5.70164913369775));
#679=CARTESIAN_POINT('',(18.3950713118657,4.32282715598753,5.94942196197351));
#680=CARTESIAN_POINT('',(18.8044052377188,3.71172889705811,6.34252648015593));
#681=CARTESIAN_POINT('',(18.9655552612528,3.43398196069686,6.49784259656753));
#682=CARTESIAN_POINT('',(19.181432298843,2.99337467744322,6.70632441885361));
#683=CARTESIAN_POINT('',(19.2490767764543,2.84252721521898,6.77172995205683));
#684=CARTESIAN_POINT('',(19.374782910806,2.53329365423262,6.8933770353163));
#685=CARTESIAN_POINT('',(19.4328459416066,2.37490864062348,6.94961989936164));
#686=CARTESIAN_POINT('',(19.5304635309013,2.07561872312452,7.04423746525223));
#687=CARTESIAN_POINT('',(19.5714872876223,1.93563802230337,7.08402632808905));
#688=CARTESIAN_POINT('',(19.6452503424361,1.65151632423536,7.15559876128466));
#689=CARTESIAN_POINT('',(19.6779911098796,1.50737606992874,7.1873837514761));
#690=CARTESIAN_POINT('',(19.7346508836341,1.21581680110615,7.2424055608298));
#691=CARTESIAN_POINT('',(19.7585732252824,1.06839904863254,7.26564561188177));
#692=CARTESIAN_POINT('',(19.7971926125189,0.771222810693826,7.30317007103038));
#693=CARTESIAN_POINT('',(19.8118895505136,0.62146429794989,7.31745437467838));
#694=CARTESIAN_POINT('',(19.8318110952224,0.320293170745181,7.33681776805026));
#695=CARTESIAN_POINT('',(19.8370086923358,0.16887706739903,7.34187060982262));
#696=CARTESIAN_POINT('',(19.8377487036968,-0.134001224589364,7.34258997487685));
#697=CARTESIAN_POINT('',(19.8332911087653,-0.285463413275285,7.33825648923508));
#698=CARTESIAN_POINT('',(19.8148058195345,-0.587261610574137,7.32028880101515));
#699=CARTESIAN_POINT('',(19.8007769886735,-0.737597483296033,7.30665349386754));
#700=CARTESIAN_POINT('',(19.7634132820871,-1.03599463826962,7.27034791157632));
#701=CARTESIAN_POINT('',(19.7400784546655,-1.18405593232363,7.24767768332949));
#702=CARTESIAN_POINT('',(19.6856648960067,-1.47084082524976,7.19483457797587));
#703=CARTESIAN_POINT('',(19.6549461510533,-1.60969741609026,7.16501057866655));
#704=CARTESIAN_POINT('',(19.5858043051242,-1.88365940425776,7.09791538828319));
#705=CARTESIAN_POINT('',(19.5473782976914,-2.0187633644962,7.06064138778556));
#706=CARTESIAN_POINT('',(19.4213104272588,-2.41743388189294,6.93842594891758));
#707=CARTESIAN_POINT('',(19.3228435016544,-2.67453979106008,6.84305682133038));
#708=CARTESIAN_POINT('',(19.1350038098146,-3.09338853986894,6.66146046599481));
#709=CARTESIAN_POINT('',(19.0517777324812,-3.26058554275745,6.58108631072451));
#710=CARTESIAN_POINT('',(18.8749398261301,-3.58421264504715,6.41057781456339));
#711=CARTESIAN_POINT('',(18.7813246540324,-3.74063925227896,6.32044033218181));
#712=CARTESIAN_POINT('',(18.4865598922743,-4.1938316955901,6.03717195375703));
#713=CARTESIAN_POINT('',(18.2717160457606,-4.47402349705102,5.83140329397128));
#714=CARTESIAN_POINT('',(17.88697452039,-4.90852074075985,5.46521601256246));
#715=CARTESIAN_POINT('',(17.7242079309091,-5.07469443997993,5.31090272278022));
#716=CARTESIAN_POINT('',(17.3877782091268,-5.38700906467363,4.99382234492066));
#717=CARTESIAN_POINT('',(17.2141101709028,-5.5331408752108,4.83105145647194));
#718=CARTESIAN_POINT('',(16.8576347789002,-5.8057635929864,4.49974939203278));
#719=CARTESIAN_POINT('',(16.6748363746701,-5.93227325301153,4.33122390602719));
#720=CARTESIAN_POINT('',(16.3007993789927,-6.16647287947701,3.99073145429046));
#721=CARTESIAN_POINT('',(16.1095640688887,-6.27417008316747,3.81876584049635));
#722=CARTESIAN_POINT('',(15.7148919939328,-6.47323355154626,3.47083699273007));
#723=CARTESIAN_POINT('',(15.5112937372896,-6.56425596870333,3.29485923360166));
#724=CARTESIAN_POINT('',(15.1979611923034,-6.68694525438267,3.03360027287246));
#725=CARTESIAN_POINT('',(15.0920943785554,-6.72556315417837,2.94688744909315));
#726=CARTESIAN_POINT('',(14.8772885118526,-6.79814399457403,2.77534497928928));
#727=CARTESIAN_POINT('',(14.7683499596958,-6.83210768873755,2.69051503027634));
#728=CARTESIAN_POINT('',(14.566095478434,-6.88978953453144,2.53867003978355));
#729=CARTESIAN_POINT('',(14.4733846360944,-6.91426031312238,2.47113678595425));
#730=CARTESIAN_POINT('',(14.2847941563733,-6.95990813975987,2.33948155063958));
#731=CARTESIAN_POINT('',(14.1889153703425,-6.98108606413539,2.27535866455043));
#732=CARTESIAN_POINT('',(13.9933977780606,-7.01993706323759,2.15250204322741));
#733=CARTESIAN_POINT('',(13.8937697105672,-7.03761935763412,2.09375435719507));
#734=CARTESIAN_POINT('',(13.6896112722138,-7.06921453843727,1.98446050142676));
#735=CARTESIAN_POINT('',(13.5850884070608,-7.0831329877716,1.93390227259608));
#736=CARTESIAN_POINT('',(13.3743659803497,-7.10623042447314,1.84717808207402));
#737=CARTESIAN_POINT('',(13.2683918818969,-7.11557348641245,1.81052656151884));
#738=CARTESIAN_POINT('',(13.05184381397,-7.12953385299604,1.7547946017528));
#739=CARTESIAN_POINT('',(12.941296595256,-7.13417545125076,1.73562388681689));
#740=CARTESIAN_POINT('',(12.7867449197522,-7.13700904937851,1.72386624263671));
#741=CARTESIAN_POINT('',(12.7433759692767,-7.1374092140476,1.72219236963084));
#742=CARTESIAN_POINT('',(12.7,-7.13740000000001,1.72225752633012));
#743=B_SPLINE_CURVE_WITH_KNOTS('',3,(#647,#648,#649,#650,#651,#652,#653,#654,#655,#656,#657,
#658,#659,#660,#661,#662,#663,#664,#665,#666,#667,#668,#669,#670,#671,#672,#673,#674,#675,#676,
#677,#678,#679,#680,#681,#682,#683,#684,#685,#686,#687,#688,#689,#690,#691,#692,#693,#694,#695,
#696,#697,#698,#699,#700,#701,#702,#703,#704,#705,#706,#707,#708,#709,#710,#711,#712,#713,#714,
#715,#716,#717,#718,#719,#720,#721,#722,#723,#724,#725,#726,#727,#728,#729,#730,#731,#732,#733,
#734,#735,#736,#737,#738,#739,#740,#741,#742),.UNSPECIFIED.,.F.,.F.,(4,2,2,2,2,2,2,2,2,2,2,2,2,
2,2,2,2,2,2,2,2,2,2,2,2,2,2,2,2,2,2,2,2,2,2,2,2,2,2,2,2,2,2,2,2,2,2,4),(0.,0.178562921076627,
0.356557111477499,0.70488594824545,0.996848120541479,1.28904230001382,1.58528923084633,
1.88144451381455,2.33370880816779,2.78613932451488,3.23910532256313,3.69212369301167,
4.59499217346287,5.49713265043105,6.21510009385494,6.93316578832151,8.36598334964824,
9.43185513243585,9.96466378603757,10.4973959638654,10.9505286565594,11.4035809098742,
11.8564616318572,12.3093476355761,12.7635193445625,13.2176914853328,13.6719175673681,
14.1261412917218,14.5615886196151,14.9972004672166,15.8678681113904,16.4771106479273,
17.086549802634,18.3071429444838,19.1436376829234,19.9805116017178,20.8165807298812,
21.6523275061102,22.5037355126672,22.9302175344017,23.3566304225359,23.7083679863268,
24.0600117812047,24.410715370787,24.7608977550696,25.0973841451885,25.432122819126,
25.5622212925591),.UNSPECIFIED.);
#744=CARTESIAN_POINT('',(12.7,7.13740000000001,1.7222575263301));
#745=VERTEX_POINT('',#744);
#746=CARTESIAN_POINT('',(12.7,-7.13740000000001,1.7222575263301));
#747=VERTEX_POINT('',#746);
#748=EDGE_CURVE('E44',#745,#747,#743,.T.);
#749=ORIENTED_EDGE('',*,*,#748,.T.);
#750=CARTESIAN_POINT('',(13.5329643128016,-7.08862816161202,5.0930048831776));
#751=CARTESIAN_POINT('',(13.4626435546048,-7.09690189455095,4.88085205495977));
#752=CARTESIAN_POINT('',(13.3945755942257,-7.10382787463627,4.66788738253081));
#753=CARTESIAN_POINT('',(13.2636523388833,-7.11541181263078,4.23900856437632));
#754=CARTESIAN_POINT('',(13.2008281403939,-7.12005694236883,4.02308460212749));
#755=CARTESIAN_POINT('',(13.0439381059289,-7.1297752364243,3.45083209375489));
#756=CARTESIAN_POINT('',(12.955538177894,-7.13322780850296,3.09288740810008));
#757=CARTESIAN_POINT('',(12.8027630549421,-7.13707475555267,2.37170623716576));
#758=CARTESIAN_POINT('',(12.7383883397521,-7.13746906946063,2.00846964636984));
#759=CARTESIAN_POINT('',(12.664565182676,-7.13735315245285,1.46143312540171));
#760=CARTESIAN_POINT('',(12.6437688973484,-7.13719776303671,1.2791399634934));
#761=CARTESIAN_POINT('',(12.6102366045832,-7.13685564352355,0.913822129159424));
#762=CARTESIAN_POINT('',(12.5974996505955,-7.13666891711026,0.73079754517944));
#763=CARTESIAN_POINT('',(12.5804988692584,-7.13640469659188,0.364391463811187));
#764=CARTESIAN_POINT('',(12.5762331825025,-7.13632717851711,0.181010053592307));
#765=CARTESIAN_POINT('',(12.5763045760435,-7.1363277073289,-0.185737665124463));
#766=CARTESIAN_POINT('',(12.5806412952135,-7.13640574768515,-0.369103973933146));
#767=CARTESIAN_POINT('',(12.602077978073,-7.13674181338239,-0.826956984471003));
#768=CARTESIAN_POINT('',(12.624471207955,-7.13707027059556,-1.10120796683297));
#769=CARTESIAN_POINT('',(12.6867754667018,-7.13745381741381,-1.64765977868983));
#770=CARTESIAN_POINT('',(12.7266869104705,-7.13750890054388,-1.91986055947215));
#771=CARTESIAN_POINT('',(12.8218429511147,-7.13651834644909,-2.46280179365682));
#772=CARTESIAN_POINT('',(12.877156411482,-7.13546770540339,-2.73352998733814));
#773=CARTESIAN_POINT('',(13.0004079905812,-7.1313415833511,-3.27204765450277));
#774=CARTESIAN_POINT('',(13.0683465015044,-7.12826603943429,-3.5398370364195));
#775=CARTESIAN_POINT('',(13.2385083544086,-7.11771925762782,-4.16055427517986));
#776=CARTESIAN_POINT('',(13.3446436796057,-7.10913158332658,-4.51238516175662));
#777=CARTESIAN_POINT('',(13.5701534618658,-7.08506810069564,-5.21158370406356));
#778=CARTESIAN_POINT('',(13.6895314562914,-7.06959044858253,-5.55895013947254));
#779=CARTESIAN_POINT('',(13.9380855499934,-7.03032577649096,-6.2500966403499));
#780=CARTESIAN_POINT('',(14.0672721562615,-7.00652974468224,-6.59387239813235));
#781=CARTESIAN_POINT('',(14.3326853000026,-6.94947865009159,-7.2778531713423));
#782=CARTESIAN_POINT('',(14.4689110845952,-6.91622459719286,-7.61805856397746));
#783=CARTESIAN_POINT('',(14.7462272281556,-6.83930646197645,-8.29460218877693));
#784=CARTESIAN_POINT('',(14.8873087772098,-6.79566046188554,-8.63094608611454));
#785=CARTESIAN_POINT('',(15.173088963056,-6.6969526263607,-9.3004423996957));
#786=CARTESIAN_POINT('',(15.3177878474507,-6.64189000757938,-9.63359459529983));
#787=CARTESIAN_POINT('',(15.6094666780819,-6.51939307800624,-10.2962157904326));
#788=CARTESIAN_POINT('',(15.7564442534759,-6.45197092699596,-10.6256880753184));
#789=CARTESIAN_POINT('',(16.0518010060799,-6.30358894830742,-11.2808994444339));
#790=CARTESIAN_POINT('',(16.2001799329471,-6.22263149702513,-11.606639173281));
#791=CARTESIAN_POINT('',(16.4073132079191,-6.09942085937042,-12.0576145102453));
#792=CARTESIAN_POINT('',(16.4658662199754,-6.06345901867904,-12.1846811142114));
#793=CARTESIAN_POINT('',(16.5829925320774,-5.98912887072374,-12.4380969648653));
#794=CARTESIAN_POINT('',(16.6415658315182,-5.95076062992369,-12.5644462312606));
#795=CARTESIAN_POINT('',(16.8171999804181,-5.83190337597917,-12.9422644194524));
#796=CARTESIAN_POINT('',(16.9342076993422,-5.74764258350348,-13.1925746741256));
#797=CARTESIAN_POINT('',(17.0509153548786,-5.65791607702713,-13.4411031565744));
#798=B_SPLINE_CURVE_WITH_KNOTS('',3,(#750,#751,#752,#753,#754,#755,#756,#757,#758,#759,#760,
#761,#762,#763,#764,#765,#766,#767,#768,#769,#770,#771,#772,#773,#774,#775,#776,#777,#778,#779,
#780,#781,#782,#783,#784,#785,#786,#787,#788,#789,#790,#791,#792,#793,#794,#795,#796,#797),
.UNSPECIFIED.,.F.,.F.,(4,2,2,2,2,2,2,2,2,2,2,2,2,2,2,2,2,2,2,2,2,2,2,4),(0.,0.670964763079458,
1.34566119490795,2.4511703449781,3.55670156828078,4.10697638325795,4.65718655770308,
5.207275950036,5.75734225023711,6.58216915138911,7.40701558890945,8.23561088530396,
9.06423192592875,10.1665726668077,11.2692085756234,12.3730427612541,13.4767591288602,
14.5785688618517,15.6804542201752,16.7812612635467,17.8818752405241,18.3152275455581,
18.7485678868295,19.6150074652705),.UNSPECIFIED.);
#799=CARTESIAN_POINT('',(12.7,-7.13740000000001,-1.7222575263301));
#800=VERTEX_POINT('',#799);
#801=EDGE_CURVE('E11',#747,#800,#798,.T.);
#802=ORIENTED_EDGE('',*,*,#801,.T.);
#803=CARTESIAN_POINT('',(12.7,-7.13740000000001,-1.72225752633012));
#804=CARTESIAN_POINT('',(12.7595870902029,-7.13740780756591,-1.72219425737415));
#805=CARTESIAN_POINT('',(12.8191089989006,-7.13665371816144,-1.72535095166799));
#806=CARTESIAN_POINT('',(12.9373255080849,-7.13369560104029,-1.73755665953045));
#807=CARTESIAN_POINT('',(12.996022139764,-7.1314961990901,-1.74658687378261));
#808=CARTESIAN_POINT('',(13.1679033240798,-7.12295687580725,-1.78120041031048));
#809=CARTESIAN_POINT('',(13.2794774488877,-7.11466879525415,-1.81435476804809));
#810=CARTESIAN_POINT('',(13.4789752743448,-7.09535627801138,-1.88832491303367));
#811=CARTESIAN_POINT('',(13.5678044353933,-7.08499166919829,-1.92703275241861));
#812=CARTESIAN_POINT('',(13.7417729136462,-7.06150716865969,-2.01138947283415));
#813=CARTESIAN_POINT('',(13.8269092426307,-7.04838509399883,-2.05704384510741));
#814=CARTESIAN_POINT('',(13.9951261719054,-7.01943851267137,-2.15376824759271));
#815=CARTESIAN_POINT('',(14.0781618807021,-7.00357904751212,-2.20490461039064));
#816=CARTESIAN_POINT('',(14.2415025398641,-6.969447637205,-2.31052718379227));
#817=CARTESIAN_POINT('',(14.3218083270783,-6.95117643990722,-2.36501235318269));
#818=CARTESIAN_POINT('',(14.5219562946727,-6.9020636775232,-2.50564353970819));
#819=CARTESIAN_POINT('',(14.6403255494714,-6.86967276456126,-2.59333965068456));
#820=CARTESIAN_POINT('',(14.8731228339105,-6.7996160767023,-2.77183896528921));
#821=CARTESIAN_POINT('',(14.9875493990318,-6.76194836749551,-2.86264329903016));
#822=CARTESIAN_POINT('',(15.2132879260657,-6.68133530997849,-3.04605562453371));
#823=CARTESIAN_POINT('',(15.3245960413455,-6.63838376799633,-3.13866562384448));
#824=CARTESIAN_POINT('',(15.5443880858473,-6.54721927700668,-3.32465173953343));
#825=CARTESIAN_POINT('',(15.6528716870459,-6.49900572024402,-3.41802794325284));
#826=CARTESIAN_POINT('',(15.973744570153,-6.34673745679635,-3.69763002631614));
#827=CARTESIAN_POINT('',(16.1823413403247,-6.23477367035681,-3.88398153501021));
#828=CARTESIAN_POINT('',(16.5895359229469,-5.98919216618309,-4.25292562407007));
#829=CARTESIAN_POINT('',(16.7881416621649,-5.85559198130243,-4.43552111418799));
#830=CARTESIAN_POINT('',(17.1351778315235,-5.59540755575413,-4.75748883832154));
#831=CARTESIAN_POINT('',(17.2855741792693,-5.47295915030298,-4.89807499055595));
#832=CARTESIAN_POINT('',(17.5786935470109,-5.21336629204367,-5.17352108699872));
#833=CARTESIAN_POINT('',(17.7214155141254,-5.07621983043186,-5.30838024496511));
#834=CARTESIAN_POINT('',(18.1360240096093,-4.64240256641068,-5.70164913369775));
#835=CARTESIAN_POINT('',(18.3950713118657,-4.32282715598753,-5.94942196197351));
#836=CARTESIAN_POINT('',(18.8044052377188,-3.71172889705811,-6.34252648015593));
#837=CARTESIAN_POINT('',(18.9655552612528,-3.43398196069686,-6.49784259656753));
#838=CARTESIAN_POINT('',(19.181432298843,-2.99337467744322,-6.70632441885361));
#839=CARTESIAN_POINT('',(19.2490767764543,-2.84252721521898,-6.77172995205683));
#840=CARTESIAN_POINT('',(19.374782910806,-2.53329365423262,-6.8933770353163));
#841=CARTESIAN_POINT('',(19.4328459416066,-2.37490864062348,-6.94961989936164));
#842=CARTESIAN_POINT('',(19.5304635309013,-2.07561872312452,-7.04423746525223));
#843=CARTESIAN_POINT('',(19.5714872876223,-1.93563802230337,-7.08402632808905));
#844=CARTESIAN_POINT('',(19.6452503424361,-1.65151632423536,-7.15559876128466));
#845=CARTESIAN_POINT('',(19.6779911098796,-1.50737606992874,-7.1873837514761));
#846=CARTESIAN_POINT('',(19.7346508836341,-1.21581680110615,-7.2424055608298));
#847=CARTESIAN_POINT('',(19.7585732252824,-1.06839904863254,-7.26564561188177));
#848=CARTESIAN_POINT('',(19.7971926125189,-0.771222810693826,-7.30317007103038));
#849=CARTESIAN_POINT('',(19.8118895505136,-0.62146429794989,-7.31745437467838));
#850=CARTESIAN_POINT('',(19.8318110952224,-0.320293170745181,-7.33681776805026));
#851=CARTESIAN_POINT('',(19.8370086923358,-0.16887706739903,-7.34187060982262));
#852=CARTESIAN_POINT('',(19.8377487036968,0.134001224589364,-7.34258997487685));
#853=CARTESIAN_POINT('',(19.8332911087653,0.285463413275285,-7.33825648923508));
#854=CARTESIAN_POINT('',(19.8148058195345,0.587261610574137,-7.32028880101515));
#855=CARTESIAN_POINT('',(19.8007769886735,0.737597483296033,-7.30665349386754));
#856=CARTESIAN_POINT('',(19.7634132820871,1.03599463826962,-7.27034791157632));
#857=CARTESIAN_POINT('',(19.7400784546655,1.18405593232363,-7.24767768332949));
#858=CARTESIAN_POINT('',(19.6856648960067,1.47084082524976,-7.19483457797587));
#859=CARTESIAN_POINT('',(19.6549461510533,1.60969741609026,-7.16501057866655));
#860=CARTESIAN_POINT('',(19.5858043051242,1.88365940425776,-7.09791538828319));
#861=CARTESIAN_POINT('',(19.5473782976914,2.0187633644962,-7.06064138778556));
#862=CARTESIAN_POINT('',(19.4213104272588,2.41743388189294,-6.93842594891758));
#863=CARTESIAN_POINT('',(19.3228435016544,2.67453979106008,-6.84305682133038));
#864=CARTESIAN_POINT('',(19.1350038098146,3.09338853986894,-6.66146046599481));
#865=CARTESIAN_POINT('',(19.0517777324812,3.26058554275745,-6.58108631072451));
#866=CARTESIAN_POINT('',(18.8749398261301,3.58421264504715,-6.41057781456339));
#867=CARTESIAN_POINT('',(18.7813246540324,3.74063925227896,-6.32044033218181));
#868=CARTESIAN_POINT('',(18.4865598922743,4.1938316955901,-6.03717195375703));
#869=CARTESIAN_POINT('',(18.2717160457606,4.47402349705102,-5.83140329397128));
#870=CARTESIAN_POINT('',(17.88697452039,4.90852074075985,-5.46521601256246));
#871=CARTESIAN_POINT('',(17.7242079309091,5.07469443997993,-5.31090272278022));
#872=CARTESIAN_POINT('',(17.3877782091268,5.38700906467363,-4.99382234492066));
#873=CARTESIAN_POINT('',(17.2141101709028,5.5331408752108,-4.83105145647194));
#874=CARTESIAN_POINT('',(16.8576347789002,5.8057635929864,-4.49974939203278));
#875=CARTESIAN_POINT('',(16.6748363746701,5.93227325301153,-4.33122390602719));
#876=CARTESIAN_POINT('',(16.3007993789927,6.16647287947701,-3.99073145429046));
#877=CARTESIAN_POINT('',(16.1095640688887,6.27417008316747,-3.81876584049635));
#878=CARTESIAN_POINT('',(15.7148919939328,6.47323355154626,-3.47083699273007));
#879=CARTESIAN_POINT('',(15.5112937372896,6.56425596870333,-3.29485923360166));
#880=CARTESIAN_POINT('',(15.1979611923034,6.68694525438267,-3.03360027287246));
#881=CARTESIAN_POINT('',(15.0920943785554,6.72556315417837,-2.94688744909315));
#882=CARTESIAN_POINT('',(14.8772885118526,6.79814399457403,-2.77534497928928));
#883=CARTESIAN_POINT('',(14.7683499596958,6.83210768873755,-2.69051503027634));
#884=CARTESIAN_POINT('',(14.566095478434,6.88978953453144,-2.53867003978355));
#885=CARTESIAN_POINT('',(14.4733846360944,6.91426031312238,-2.47113678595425));
#886=CARTESIAN_POINT('',(14.2847941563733,6.95990813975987,-2.33948155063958));
#887=CARTESIAN_POINT('',(14.1889153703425,6.98108606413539,-2.27535866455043));
#888=CARTESIAN_POINT('',(13.9933977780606,7.01993706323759,-2.15250204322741));
#889=CARTESIAN_POINT('',(13.8937697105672,7.03761935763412,-2.09375435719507));
#890=CARTESIAN_POINT('',(13.6896112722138,7.06921453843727,-1.98446050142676));
#891=CARTESIAN_POINT('',(13.5850884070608,7.0831329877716,-1.93390227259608));
#892=CARTESIAN_POINT('',(13.3743659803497,7.10623042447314,-1.84717808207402));
#893=CARTESIAN_POINT('',(13.2683918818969,7.11557348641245,-1.81052656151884));
#894=CARTESIAN_POINT('',(13.05184381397,7.12953385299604,-1.7547946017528));
#895=CARTESIAN_POINT('',(12.941296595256,7.13417545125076,-1.73562388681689));
#896=CARTESIAN_POINT('',(12.7867449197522,7.13700904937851,-1.72386624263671));
#897=CARTESIAN_POINT('',(12.7433759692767,7.1374092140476,-1.72219236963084));
#898=CARTESIAN_POINT('',(12.7,7.13740000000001,-1.72225752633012));
#899=B_SPLINE_CURVE_WITH_KNOTS('',3,(#803,#804,#805,#806,#807,#808,#809,#810,#811,#812,#813,
#814,#815,#816,#817,#818,#819,#820,#821,#822,#823,#824,#825,#826,#827,#828,#829,#830,#831,#832,
#833,#834,#835,#836,#837,#838,#839,#840,#841,#842,#843,#844,#845,#846,#847,#848,#849,#850,#851,
#852,#853,#854,#855,#856,#857,#858,#859,#860,#861,#862,#863,#864,#865,#866,#867,#868,#869,#870,
#871,#872,#873,#874,#875,#876,#877,#878,#879,#880,#881,#882,#883,#884,#885,#886,#887,#888,#889,
#890,#891,#892,#893,#894,#895,#896,#897,#898),.UNSPECIFIED.,.F.,.F.,(4,2,2,2,2,2,2,2,2,2,2,2,2,
2,2,2,2,2,2,2,2,2,2,2,2,2,2,2,2,2,2,2,2,2,2,2,2,2,2,2,2,2,2,2,2,2,2,4),(0.,0.178562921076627,
0.356557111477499,0.70488594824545,0.996848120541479,1.28904230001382,1.58528923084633,
1.88144451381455,2.33370880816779,2.78613932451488,3.23910532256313,3.69212369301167,
4.59499217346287,5.49713265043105,6.21510009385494,6.93316578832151,8.36598334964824,
9.43185513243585,9.96466378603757,10.4973959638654,10.9505286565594,11.4035809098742,
11.8564616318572,12.3093476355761,12.7635193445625,13.2176914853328,13.6719175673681,
14.1261412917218,14.5615886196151,14.9972004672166,15.8678681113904,16.4771106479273,
17.086549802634,18.3071429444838,19.1436376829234,19.9805116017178,20.8165807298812,
21.6523275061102,22.5037355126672,22.9302175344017,23.3566304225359,23.7083679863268,
24.0600117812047,24.410715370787,24.7608977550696,25.0973841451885,25.432122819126,
25.5622212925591),.UNSPECIFIED.);
#900=CARTESIAN_POINT('',(12.7,7.13740000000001,-1.7222575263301));
#901=VERTEX_POINT('',#900);
#902=EDGE_CURVE('E117',#800,#901,#899,.T.);
#903=ORIENTED_EDGE('',*,*,#902,.T.);
#904=CARTESIAN_POINT('',(13.5329643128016,7.08862816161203,-5.0930048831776));
#905=CARTESIAN_POINT('',(13.4626435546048,7.09690189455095,-4.88085205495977));
#906=CARTESIAN_POINT('',(13.3945755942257,7.10382787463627,-4.66788738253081));
#907=CARTESIAN_POINT('',(13.2636523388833,7.11541181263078,-4.23900856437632));
#908=CARTESIAN_POINT('',(13.2008281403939,7.12005694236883,-4.02308460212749));
#909=CARTESIAN_POINT('',(13.0439381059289,7.1297752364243,-3.4508320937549));
#910=CARTESIAN_POINT('',(12.955538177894,7.13322780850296,-3.09288740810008));
#911=CARTESIAN_POINT('',(12.8027630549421,7.13707475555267,-2.37170623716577));
#912=CARTESIAN_POINT('',(12.7383883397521,7.13746906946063,-2.00846964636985));
#913=CARTESIAN_POINT('',(12.664565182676,7.13735315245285,-1.46143312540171));
#914=CARTESIAN_POINT('',(12.6437688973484,7.13719776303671,-1.27913996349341));
#915=CARTESIAN_POINT('',(12.6102366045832,7.13685564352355,-0.913822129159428));
#916=CARTESIAN_POINT('',(12.5974996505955,7.13666891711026,-0.730797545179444));
#917=CARTESIAN_POINT('',(12.5804988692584,7.13640469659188,-0.364391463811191));
#918=CARTESIAN_POINT('',(12.5762331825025,7.13632717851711,-0.181010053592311));
#919=CARTESIAN_POINT('',(12.5763045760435,7.1363277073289,0.185737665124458));
#920=CARTESIAN_POINT('',(12.5806412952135,7.13640574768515,0.369103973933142));
#921=CARTESIAN_POINT('',(12.602077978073,7.13674181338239,0.826956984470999));
#922=CARTESIAN_POINT('',(12.624471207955,7.13707027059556,1.10120796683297));
#923=CARTESIAN_POINT('',(12.6867754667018,7.13745381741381,1.64765977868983));
#924=CARTESIAN_POINT('',(12.7266869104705,7.13750890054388,1.91986055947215));
#925=CARTESIAN_POINT('',(12.8218429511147,7.13651834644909,2.46280179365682));
#926=CARTESIAN_POINT('',(12.877156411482,7.13546770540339,2.73352998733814));
#927=CARTESIAN_POINT('',(13.0004079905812,7.1313415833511,3.27204765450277));
#928=CARTESIAN_POINT('',(13.0683465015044,7.12826603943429,3.5398370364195));
#929=CARTESIAN_POINT('',(13.2385083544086,7.11771925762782,4.16055427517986));
#930=CARTESIAN_POINT('',(13.3446436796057,7.10913158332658,4.51238516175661));
#931=CARTESIAN_POINT('',(13.5701534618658,7.08506810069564,5.21158370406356));
#932=CARTESIAN_POINT('',(13.6895314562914,7.06959044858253,5.55895013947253));
#933=CARTESIAN_POINT('',(13.9380855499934,7.03032577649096,6.2500966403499));
#934=CARTESIAN_POINT('',(14.0672721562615,7.00652974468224,6.59387239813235));
#935=CARTESIAN_POINT('',(14.3326853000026,6.94947865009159,7.2778531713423));
#936=CARTESIAN_POINT('',(14.4689110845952,6.91622459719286,7.61805856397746));
#937=CARTESIAN_POINT('',(14.7462272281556,6.83930646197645,8.29460218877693));
#938=CARTESIAN_POINT('',(14.8873087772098,6.79566046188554,8.63094608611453));
#939=CARTESIAN_POINT('',(15.173088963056,6.6969526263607,9.3004423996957));
#940=CARTESIAN_POINT('',(15.3177878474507,6.64189000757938,9.63359459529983));
#941=CARTESIAN_POINT('',(15.6094666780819,6.51939307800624,10.2962157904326));
#942=CARTESIAN_POINT('',(15.7564442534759,6.45197092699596,10.6256880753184));
#943=CARTESIAN_POINT('',(16.0518010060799,6.30358894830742,11.2808994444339));
#944=CARTESIAN_POINT('',(16.2001799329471,6.22263149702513,11.606639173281));
#945=CARTESIAN_POINT('',(16.4073132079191,6.09942085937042,12.0576145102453));
#946=CARTESIAN_POINT('',(16.4658662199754,6.06345901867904,12.1846811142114));
#947=CARTESIAN_POINT('',(16.5829925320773,5.98912887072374,12.4380969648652));
#948=CARTESIAN_POINT('',(16.6415658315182,5.95076062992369,12.5644462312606));
#949=CARTESIAN_POINT('',(16.8171999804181,5.83190337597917,12.9422644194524));
#950=CARTESIAN_POINT('',(16.9342076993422,5.74764258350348,13.1925746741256));
#951=CARTESIAN_POINT('',(17.0509153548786,5.65791607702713,13.4411031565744));
#952=B_SPLINE_CURVE_WITH_KNOTS('',3,(#904,#905,#906,#907,#908,#909,#910,#911,#912,#913,#914,
#915,#916,#917,#918,#919,#920,#921,#922,#923,#924,#925,#926,#927,#928,#929,#930,#931,#932,#933,
#934,#935,#936,#937,#938,#939,#940,#941,#942,#943,#944,#945,#946,#947,#948,#949,#950,#951),
.UNSPECIFIED.,.F.,.F.,(4,2,2,2,2,2,2,2,2,2,2,2,2,2,2,2,2,2,2,2,2,2,2,4),(0.,0.670964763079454,
1.34566119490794,2.45117034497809,3.55670156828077,4.10697638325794,4.65718655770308,
5.20727595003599,5.7573422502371,6.5821691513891,7.40701558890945,8.23561088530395,
9.06423192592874,10.1665726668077,11.2692085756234,12.3730427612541,13.4767591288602,
14.5785688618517,15.6804542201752,16.7812612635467,17.881875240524,18.3152275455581,
18.7485678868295,19.6150074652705),.UNSPECIFIED.);
#953=EDGE_CURVE('E112',#901,#745,#952,.T.);
#954=ORIENTED_EDGE('',*,*,#953,.T.);
#955=EDGE_LOOP('',(#749,#802,#903,#954));
#956=FACE_BOUND('',#955,.T.);
#957=CARTESIAN_POINT('',(12.7,0.,8.71982000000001));
#958=DIRECTION('',(0.,0.,1.));
#959=DIRECTION('',(1.,0.,0.));
#960=AXIS2_PLACEMENT_3D('',#957,#958,#959);
#961=CIRCLE('',#960,7.13740000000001);
#962=CARTESIAN_POINT('',(19.8374,0.,8.71982000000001));
#963=VERTEX_POINT('',#962);
#964=EDGE_CURVE('E193',#963,#963,#961,.T.);
#965=ORIENTED_EDGE('',*,*,#964,.T.);
#966=EDGE_LOOP('',(#965));
#967=FACE_BOUND('',#966,.T.);
#968=CARTESIAN_POINT('',(12.7,0.,-8.71982000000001));
#969=DIRECTION('',(0.,0.,-1.));
#970=DIRECTION('',(0.,1.,0.));
#971=AXIS2_PLACEMENT_3D('',#968,#969,#970);
#972=CIRCLE('',#971,7.13740000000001);
#973=CARTESIAN_POINT('',(12.7,7.13740000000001,-8.71982));
#974=VERTEX_POINT('',#973);
#975=EDGE_CURVE('E184',#974,#974,#972,.T.);
#976=ORIENTED_EDGE('',*,*,#975,.T.);
#977=EDGE_LOOP('',(#976));
#978=FACE_BOUND('',#977,.T.);
#979=ADVANCED_FACE('F127',(#956,#967,#978),#646,.F.);
#980=CARTESIAN_POINT('',(19.8374,0.,8.71982000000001));
#981=DIRECTION('',(0.,0.,-1.));
#982=DIRECTION('',(-1.,0.,0.));
#983=AXIS2_PLACEMENT_3D('',#980,#981,#982);
#984=PLANE('',#983);
#985=ORIENTED_EDGE('',*,*,#964,.F.);
#986=EDGE_LOOP('',(#985));
#987=FACE_BOUND('',#986,.T.);
#988=CARTESIAN_POINT('',(12.7,0.,8.71982000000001));
#989=DIRECTION('',(0.,0.,1.));
#990=DIRECTION('',(1.,0.,0.));
#991=AXIS2_PLACEMENT_3D('',#988,#989,#990);
#992=CIRCLE('',#991,8.26320057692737);
#993=CARTESIAN_POINT('',(20.9632005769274,0.,8.71982000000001));
#994=VERTEX_POINT('',#993);
#995=EDGE_CURVE('E190',#994,#994,#992,.T.);
#996=ORIENTED_EDGE('',*,*,#995,.T.);
#997=EDGE_LOOP('',(#996));
#998=FACE_BOUND('',#997,.T.);
#999=ADVANCED_FACE('F449',(#987,#998),#984,.F.);
#1000=CARTESIAN_POINT('',(12.7,0.,19.05));
#1001=DIRECTION('',(0.,0.,1.));
#1002=DIRECTION('',(1.,0.,0.));
#1003=AXIS2_PLACEMENT_3D('',#1000,#1001,#1002);
#1004=CONICAL_SURFACE('',#1003,8.5725,0.0299323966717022);
#1005=ORIENTED_EDGE('',*,*,#995,.F.);
#1006=EDGE_LOOP('',(#1005));
#1007=FACE_BOUND('',#1006,.T.);
#1008=ORIENTED_EDGE('',*,*,#59,.T.);
#1009=EDGE_LOOP('',(#1008));
#1010=FACE_BOUND('',#1009,.T.);
#1011=ADVANCED_FACE('F456',(#1007,#1010),#1004,.F.);
#1012=CARTESIAN_POINT('',(19.8374,0.,-8.71982000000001));
#1013=DIRECTION('',(0.,0.,1.));
#1014=DIRECTION('',(0.,-1.,0.));
#1015=AXIS2_PLACEMENT_3D('',#1012,#1013,#1014);
#1016=PLANE('',#1015);
#1017=ORIENTED_EDGE('',*,*,#975,.F.);
#1018=EDGE_LOOP('',(#1017));
#1019=FACE_BOUND('',#1018,.T.);
#1020=CARTESIAN_POINT('',(12.7,0.,-8.71982000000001));
#1021=DIRECTION('',(0.,0.,-1.));
#1022=DIRECTION('',(0.,1.,0.));
#1023=AXIS2_PLACEMENT_3D('',#1020,#1021,#1022);
#1024=CIRCLE('',#1023,8.26320057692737);
#1025=CARTESIAN_POINT('',(12.7,8.26320057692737,-8.71982000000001));
#1026=VERTEX_POINT('',#1025);
#1027=EDGE_CURVE('E181',#1026,#1026,#1024,.T.);
#1028=ORIENTED_EDGE('',*,*,#1027,.T.);
#1029=EDGE_LOOP('',(#1028));
#1030=FACE_BOUND('',#1029,.T.);
#1031=ADVANCED_FACE('F462',(#1019,#1030),#1016,.F.);
#1032=CARTESIAN_POINT('',(12.7,0.,-19.05));
#1033=DIRECTION('',(0.,0.,-1.));
#1034=DIRECTION('',(0.,1.,0.));
#1035=AXIS2_PLACEMENT_3D('',#1032,#1033,#1034);
#1036=CONICAL_SURFACE('',#1035,8.5725,0.0299323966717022);
#1037=ORIENTED_EDGE('',*,*,#1027,.F.);
#1038=EDGE_LOOP('',(#1037));
#1039=FACE_BOUND('',#1038,.T.);
#1040=ORIENTED_EDGE('',*,*,#183,.T.);
#1041=EDGE_LOOP('',(#1040));
#1042=FACE_BOUND('',#1041,.T.);
#1043=ADVANCED_FACE('F154',(#1039,#1042),#1036,.F.);
#1044=CARTESIAN_POINT('',(76.2,0.,0.));
#1045=DIRECTION('',(1.,0.,0.));
#1046=DIRECTION('',(0.,0.,-1.));
#1047=AXIS2_PLACEMENT_3D('',#1044,#1045,#1046);
#1048=CYLINDRICAL_SURFACE('',#1047,7.34225099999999);
#1049=CARTESIAN_POINT('',(19.9623383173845,0.,0.));
#1050=DIRECTION('',(1.,0.,0.));
#1051=DIRECTION('',(0.,0.,-1.));
#1052=AXIS2_PLACEMENT_3D('',#1049,#1050,#1051);
#1053=CIRCLE('',#1052,7.34225099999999);
#1054=CARTESIAN_POINT('',(19.9623383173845,0.,-7.34225099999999));
#1055=VERTEX_POINT('',#1054);
#1056=EDGE_CURVE('E169',#1055,#1055,#1053,.T.);
#1057=ORIENTED_EDGE('',*,*,#1056,.T.);
#1058=EDGE_LOOP('',(#1057));
#1059=FACE_BOUND('',#1058,.T.);
#1060=CARTESIAN_POINT('',(12.7,0.,0.));
#1061=DIRECTION('',(1.,0.,0.));
#1062=DIRECTION('',(0.,0.,-1.));
#1063=AXIS2_PLACEMENT_3D('',#1060,#1061,#1062);
#1064=CIRCLE('',#1063,7.34225099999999);
#1065=EDGE_CURVE('E51',#901,#745,#1064,.T.);
#1066=ORIENTED_EDGE('',*,*,#1065,.F.);
#1067=ORIENTED_EDGE('',*,*,#902,.F.);
#1068=EDGE_CURVE('E125',#747,#800,#1064,.T.);
#1069=ORIENTED_EDGE('',*,*,#1068,.F.);
#1070=ORIENTED_EDGE('',*,*,#748,.F.);
#1071=EDGE_LOOP('',(#1066,#1067,#1069,#1070));
#1072=FACE_BOUND('',#1071,.T.);
#1073=ADVANCED_FACE('F121',(#1059,#1072),#1048,.F.);
#1074=CARTESIAN_POINT('',(12.7,0.,0.));
#1075=DIRECTION('',(1.,0.,0.));
#1076=DIRECTION('',(0.,0.,-1.));
#1077=AXIS2_PLACEMENT_3D('',#1074,#1075,#1076);
#1078=CONICAL_SURFACE('',#1077,7.34225099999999,1.02974425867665);
#1079=ORIENTED_EDGE('',*,*,#1068,.T.);
#1080=ORIENTED_EDGE('',*,*,#801,.F.);
#1081=EDGE_LOOP('',(#1079,#1080));
#1082=FACE_BOUND('',#1081,.T.);
#1083=ADVANCED_FACE('F153',(#1082),#1078,.F.);
#1084=ORIENTED_EDGE('',*,*,#1065,.T.);
#1085=ORIENTED_EDGE('',*,*,#953,.F.);
#1086=EDGE_LOOP('',(#1084,#1085));
#1087=FACE_BOUND('',#1086,.T.);
#1088=ADVANCED_FACE('F113',(#1087),#1078,.F.);
#1089=CARTESIAN_POINT('',(20.32,0.,0.));
#1090=DIRECTION('',(1.,0.,0.));
#1091=DIRECTION('',(0.,0.,-1.));
#1092=AXIS2_PLACEMENT_3D('',#1089,#1090,#1091);
#1093=CONICAL_SURFACE('',#1092,7.93749999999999,1.02974425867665);
#1094=CARTESIAN_POINT('',(20.32,0.,0.));
#1095=DIRECTION('',(1.,0.,0.));
#1096=DIRECTION('',(0.,0.,-1.));
#1097=AXIS2_PLACEMENT_3D('',#1094,#1095,#1096);
#1098=CIRCLE('',#1097,7.93749999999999);
#1099=CARTESIAN_POINT('',(20.32,0.,-7.93749999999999));
#1100=VERTEX_POINT('',#1099);
#1101=EDGE_CURVE('E171',#1100,#1100,#1098,.T.);
#1102=ORIENTED_EDGE('',*,*,#1101,.T.);
#1103=EDGE_LOOP('',(#1102));
#1104=FACE_BOUND('',#1103,.T.);
#1105=ORIENTED_EDGE('',*,*,#1056,.F.);
#1106=EDGE_LOOP('',(#1105));
#1107=FACE_BOUND('',#1106,.T.);
#1108=ADVANCED_FACE('F156',(#1104,#1107),#1093,.F.);
#1109=CARTESIAN_POINT('',(76.2,0.,0.));
#1110=DIRECTION('',(1.,0.,0.));
#1111=DIRECTION('',(0.,0.,-1.));
#1112=AXIS2_PLACEMENT_3D('',#1109,#1110,#1111);
#1113=CYLINDRICAL_SURFACE('',#1112,7.93749999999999);
#1114=ORIENTED_EDGE('',*,*,#437,.T.);
#1115=EDGE_LOOP('',(#1114));
#1116=FACE_BOUND('',#1115,.T.);
#1117=ORIENTED_EDGE('',*,*,#1101,.F.);
#1118=EDGE_LOOP('',(#1117));
#1119=FACE_BOUND('',#1118,.T.);
#1120=ADVANCED_FACE('F490',(#1116,#1119),#1113,.F.);
#1121=CLOSED_SHELL('',(#46,#108,#139,#170,#212,#243,#265,#290,#304,#384,#412,#424,#452,#604,
#620,#626,#641,#979,#999,#1011,#1031,#1043,#1073,#1083,#1088,#1108,#1120));
#1122=MANIFOLD_SOLID_BREP('B2',#1121);
#1123=ADVANCED_BREP_SHAPE_REPRESENTATION('',(#18,#1122),#14);
#1124=SHAPE_DEFINITION_REPRESENTATION(#9,#1123);
ENDSEC;
END-ISO-10303-21;
